VERSION 5.7 ;
  NOWIREEXTENSIONATPIN ON ;
  DIVIDERCHAR "/" ;
  BUSBITCHARS "[]" ;
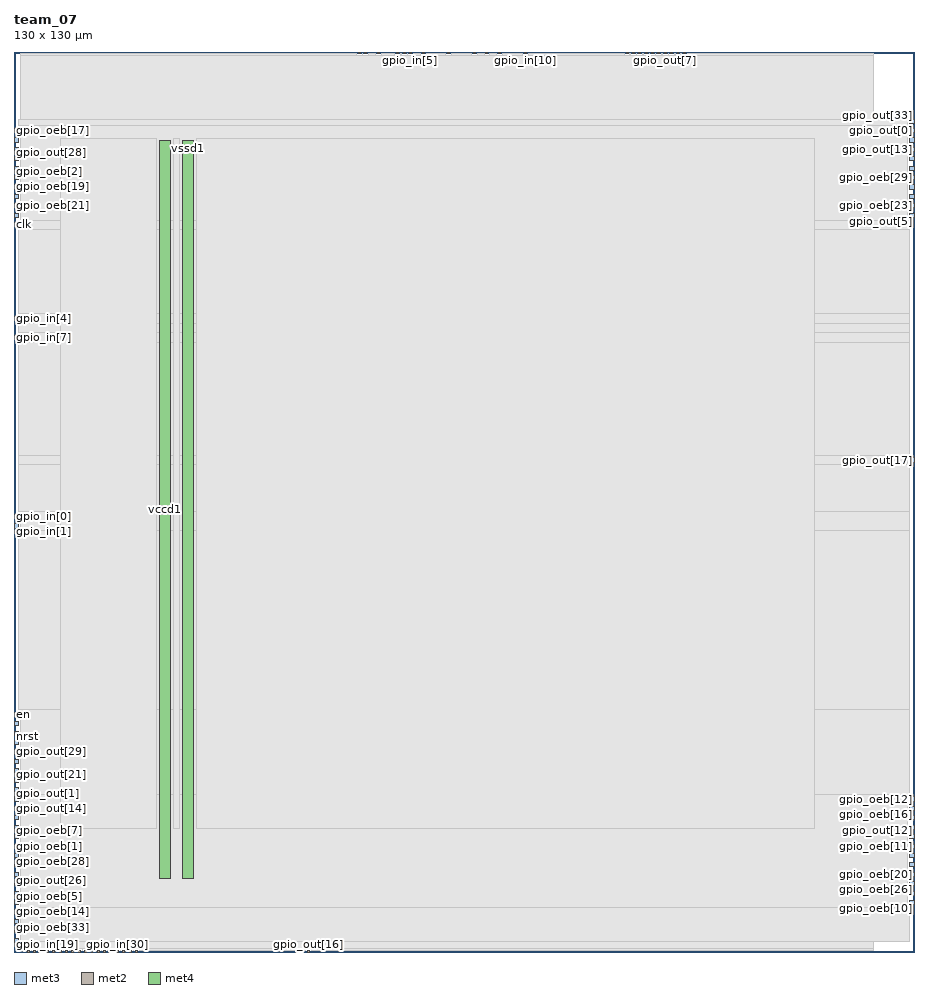
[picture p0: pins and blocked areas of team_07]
MACRO team_07
  CLASS BLOCK ;
  FOREIGN team_07 ;
  ORIGIN 0.000 0.000 ;
  SIZE 130.000 BY 130.000 ;
  PIN clk
    DIRECTION INPUT ;
    USE SIGNAL ;
    ANTENNAGATEAREA 1.286700 ;
    ANTENNADIFFAREA 0.434700 ;
    PORT
      LAYER met3 ;
        RECT 0.000 104.760 0.600 105.360 ;
    END
  END clk
  PIN en
    DIRECTION INPUT ;
    USE SIGNAL ;
    ANTENNAGATEAREA 0.647700 ;
    ANTENNADIFFAREA 0.434700 ;
    PORT
      LAYER met3 ;
        RECT 0.000 34.040 0.600 34.640 ;
    END
  END en
  PIN gpio_in[0]
    DIRECTION INPUT ;
    USE SIGNAL ;
    ANTENNAGATEAREA 0.647700 ;
    ANTENNADIFFAREA 0.434700 ;
    PORT
      LAYER met3 ;
        RECT 0.000 62.600 0.600 63.200 ;
    END
  END gpio_in[0]
  PIN gpio_in[10]
    DIRECTION INPUT ;
    USE SIGNAL ;
    ANTENNAGATEAREA 0.647700 ;
    ANTENNADIFFAREA 0.434700 ;
    PORT
      LAYER met2 ;
        RECT 73.690 129.720 73.970 130.000 ;
    END
  END gpio_in[10]
  PIN gpio_in[11]
    DIRECTION INPUT ;
    USE SIGNAL ;
    ANTENNAGATEAREA 0.647700 ;
    ANTENNADIFFAREA 0.434700 ;
    PORT
      LAYER met2 ;
        RECT 68.170 129.720 68.450 130.000 ;
    END
  END gpio_in[11]
  PIN gpio_in[12]
    DIRECTION INPUT ;
    USE SIGNAL ;
    ANTENNAGATEAREA 0.631200 ;
    ANTENNADIFFAREA 0.434700 ;
    PORT
      LAYER met2 ;
        RECT 70.010 129.720 70.290 130.000 ;
    END
  END gpio_in[12]
  PIN gpio_in[13]
    DIRECTION INPUT ;
    USE SIGNAL ;
    ANTENNAGATEAREA 0.647700 ;
    ANTENNADIFFAREA 0.434700 ;
    PORT
      LAYER met2 ;
        RECT 66.330 129.720 66.610 130.000 ;
    END
  END gpio_in[13]
  PIN gpio_in[14]
    DIRECTION INPUT ;
    USE SIGNAL ;
    ANTENNAGATEAREA 0.647700 ;
    ANTENNADIFFAREA 0.434700 ;
    PORT
      LAYER met2 ;
        RECT 58.970 129.720 59.250 130.000 ;
    END
  END gpio_in[14]
  PIN gpio_in[15]
    DIRECTION INPUT ;
    USE SIGNAL ;
    ANTENNAGATEAREA 0.647700 ;
    ANTENNADIFFAREA 0.434700 ;
    PORT
      LAYER met2 ;
        RECT 50.690 129.720 50.970 130.000 ;
    END
  END gpio_in[15]
  PIN gpio_in[16]
    DIRECTION INPUT ;
    USE SIGNAL ;
    PORT
      LAYER met2 ;
        RECT 1.930 0.000 2.210 0.280 ;
    END
  END gpio_in[16]
  PIN gpio_in[17]
    DIRECTION INPUT ;
    USE SIGNAL ;
    PORT
      LAYER met2 ;
        RECT 2.850 0.000 3.130 0.280 ;
    END
  END gpio_in[17]
  PIN gpio_in[18]
    DIRECTION INPUT ;
    USE SIGNAL ;
    PORT
      LAYER met2 ;
        RECT 3.770 0.000 4.050 0.280 ;
    END
  END gpio_in[18]
  PIN gpio_in[19]
    DIRECTION INPUT ;
    USE SIGNAL ;
    PORT
      LAYER met2 ;
        RECT 4.690 0.000 4.970 0.280 ;
    END
  END gpio_in[19]
  PIN gpio_in[1]
    DIRECTION INPUT ;
    USE SIGNAL ;
    ANTENNAGATEAREA 0.647700 ;
    ANTENNADIFFAREA 0.434700 ;
    PORT
      LAYER met3 ;
        RECT 0.000 61.240 0.600 61.840 ;
    END
  END gpio_in[1]
  PIN gpio_in[20]
    DIRECTION INPUT ;
    USE SIGNAL ;
    PORT
      LAYER met2 ;
        RECT 5.610 0.000 5.890 0.280 ;
    END
  END gpio_in[20]
  PIN gpio_in[21]
    DIRECTION INPUT ;
    USE SIGNAL ;
    PORT
      LAYER met2 ;
        RECT 6.530 0.000 6.810 0.280 ;
    END
  END gpio_in[21]
  PIN gpio_in[22]
    DIRECTION INPUT ;
    USE SIGNAL ;
    PORT
      LAYER met2 ;
        RECT 7.450 0.000 7.730 0.280 ;
    END
  END gpio_in[22]
  PIN gpio_in[23]
    DIRECTION INPUT ;
    USE SIGNAL ;
    PORT
      LAYER met2 ;
        RECT 8.370 0.000 8.650 0.280 ;
    END
  END gpio_in[23]
  PIN gpio_in[24]
    DIRECTION INPUT ;
    USE SIGNAL ;
    PORT
      LAYER met2 ;
        RECT 9.290 0.000 9.570 0.280 ;
    END
  END gpio_in[24]
  PIN gpio_in[25]
    DIRECTION INPUT ;
    USE SIGNAL ;
    PORT
      LAYER met2 ;
        RECT 10.210 0.000 10.490 0.280 ;
    END
  END gpio_in[25]
  PIN gpio_in[26]
    DIRECTION INPUT ;
    USE SIGNAL ;
    PORT
      LAYER met2 ;
        RECT 11.130 0.000 11.410 0.280 ;
    END
  END gpio_in[26]
  PIN gpio_in[27]
    DIRECTION INPUT ;
    USE SIGNAL ;
    PORT
      LAYER met2 ;
        RECT 12.050 0.000 12.330 0.280 ;
    END
  END gpio_in[27]
  PIN gpio_in[28]
    DIRECTION INPUT ;
    USE SIGNAL ;
    PORT
      LAYER met2 ;
        RECT 12.970 0.000 13.250 0.280 ;
    END
  END gpio_in[28]
  PIN gpio_in[29]
    DIRECTION INPUT ;
    USE SIGNAL ;
    PORT
      LAYER met2 ;
        RECT 13.890 0.000 14.170 0.280 ;
    END
  END gpio_in[29]
  PIN gpio_in[2]
    DIRECTION INPUT ;
    USE SIGNAL ;
    ANTENNAGATEAREA 0.647700 ;
    ANTENNADIFFAREA 0.434700 ;
    PORT
      LAYER met2 ;
        RECT 56.210 129.720 56.490 130.000 ;
    END
  END gpio_in[2]
  PIN gpio_in[30]
    DIRECTION INPUT ;
    USE SIGNAL ;
    PORT
      LAYER met2 ;
        RECT 14.810 0.000 15.090 0.280 ;
    END
  END gpio_in[30]
  PIN gpio_in[31]
    DIRECTION INPUT ;
    USE SIGNAL ;
    PORT
      LAYER met2 ;
        RECT 15.730 0.000 16.010 0.280 ;
    END
  END gpio_in[31]
  PIN gpio_in[32]
    DIRECTION INPUT ;
    USE SIGNAL ;
    PORT
      LAYER met2 ;
        RECT 16.650 0.000 16.930 0.280 ;
    END
  END gpio_in[32]
  PIN gpio_in[33]
    DIRECTION INPUT ;
    USE SIGNAL ;
    PORT
      LAYER met2 ;
        RECT 17.570 0.000 17.850 0.280 ;
    END
  END gpio_in[33]
  PIN gpio_in[3]
    DIRECTION INPUT ;
    USE SIGNAL ;
    ANTENNAGATEAREA 0.647700 ;
    ANTENNADIFFAREA 0.434700 ;
    PORT
      LAYER met2 ;
        RECT 55.290 129.720 55.570 130.000 ;
    END
  END gpio_in[3]
  PIN gpio_in[4]
    DIRECTION INPUT ;
    USE SIGNAL ;
    ANTENNAGATEAREA 0.631200 ;
    ANTENNADIFFAREA 0.434700 ;
    PORT
      LAYER met3 ;
        RECT 0.000 91.160 0.600 91.760 ;
    END
  END gpio_in[4]
  PIN gpio_in[5]
    DIRECTION INPUT ;
    USE SIGNAL ;
    ANTENNAGATEAREA 0.647700 ;
    ANTENNADIFFAREA 0.434700 ;
    PORT
      LAYER met2 ;
        RECT 57.130 129.720 57.410 130.000 ;
    END
  END gpio_in[5]
  PIN gpio_in[6]
    DIRECTION INPUT ;
    USE SIGNAL ;
    ANTENNAGATEAREA 0.647700 ;
    ANTENNADIFFAREA 0.434700 ;
    PORT
      LAYER met2 ;
        RECT 52.530 129.720 52.810 130.000 ;
    END
  END gpio_in[6]
  PIN gpio_in[7]
    DIRECTION INPUT ;
    USE SIGNAL ;
    ANTENNAGATEAREA 0.647700 ;
    ANTENNADIFFAREA 0.434700 ;
    PORT
      LAYER met3 ;
        RECT 0.000 88.440 0.600 89.040 ;
    END
  END gpio_in[7]
  PIN gpio_in[8]
    DIRECTION INPUT ;
    USE SIGNAL ;
    ANTENNAGATEAREA 0.647700 ;
    ANTENNADIFFAREA 0.434700 ;
    PORT
      LAYER met2 ;
        RECT 62.650 129.720 62.930 130.000 ;
    END
  END gpio_in[8]
  PIN gpio_in[9]
    DIRECTION INPUT ;
    USE SIGNAL ;
    ANTENNAGATEAREA 0.647700 ;
    ANTENNADIFFAREA 0.434700 ;
    PORT
      LAYER met2 ;
        RECT 49.770 129.720 50.050 130.000 ;
    END
  END gpio_in[9]
  PIN gpio_oeb[0]
    DIRECTION OUTPUT ;
    USE SIGNAL ;
    PORT
      LAYER met2 ;
        RECT 96.690 129.720 96.970 130.000 ;
    END
  END gpio_oeb[0]
  PIN gpio_oeb[10]
    DIRECTION OUTPUT ;
    USE SIGNAL ;
    PORT
      LAYER met3 ;
        RECT 129.400 6.840 130.000 7.440 ;
    END
  END gpio_oeb[10]
  PIN gpio_oeb[11]
    DIRECTION OUTPUT ;
    USE SIGNAL ;
    PORT
      LAYER met3 ;
        RECT 129.400 15.000 130.000 15.600 ;
    END
  END gpio_oeb[11]
  PIN gpio_oeb[12]
    DIRECTION OUTPUT ;
    USE SIGNAL ;
    PORT
      LAYER met3 ;
        RECT 129.400 21.800 130.000 22.400 ;
    END
  END gpio_oeb[12]
  PIN gpio_oeb[13]
    DIRECTION OUTPUT ;
    USE SIGNAL ;
    PORT
      LAYER met3 ;
        RECT 0.000 1.400 0.600 2.000 ;
    END
  END gpio_oeb[13]
  PIN gpio_oeb[14]
    DIRECTION OUTPUT ;
    USE SIGNAL ;
    PORT
      LAYER met3 ;
        RECT 0.000 5.480 0.600 6.080 ;
    END
  END gpio_oeb[14]
  PIN gpio_oeb[15]
    DIRECTION OUTPUT ;
    USE SIGNAL ;
    PORT
      LAYER met3 ;
        RECT 129.400 12.280 130.000 12.880 ;
    END
  END gpio_oeb[15]
  PIN gpio_oeb[16]
    DIRECTION OUTPUT ;
    USE SIGNAL ;
    PORT
      LAYER met3 ;
        RECT 129.400 20.440 130.000 21.040 ;
    END
  END gpio_oeb[16]
  PIN gpio_oeb[17]
    DIRECTION OUTPUT ;
    USE SIGNAL ;
    PORT
      LAYER met3 ;
        RECT 0.000 118.360 0.600 118.960 ;
    END
  END gpio_oeb[17]
  PIN gpio_oeb[18]
    DIRECTION OUTPUT ;
    USE SIGNAL ;
    PORT
      LAYER met3 ;
        RECT 0.000 12.280 0.600 12.880 ;
    END
  END gpio_oeb[18]
  PIN gpio_oeb[19]
    DIRECTION OUTPUT ;
    USE SIGNAL ;
    PORT
      LAYER met3 ;
        RECT 0.000 110.200 0.600 110.800 ;
    END
  END gpio_oeb[19]
  PIN gpio_oeb[1]
    DIRECTION OUTPUT ;
    USE SIGNAL ;
    PORT
      LAYER met3 ;
        RECT 0.000 15.000 0.600 15.600 ;
    END
  END gpio_oeb[1]
  PIN gpio_oeb[20]
    DIRECTION OUTPUT ;
    USE SIGNAL ;
    PORT
      LAYER met3 ;
        RECT 129.400 10.920 130.000 11.520 ;
    END
  END gpio_oeb[20]
  PIN gpio_oeb[21]
    DIRECTION OUTPUT ;
    USE SIGNAL ;
    PORT
      LAYER met3 ;
        RECT 0.000 107.480 0.600 108.080 ;
    END
  END gpio_oeb[21]
  PIN gpio_oeb[22]
    DIRECTION OUTPUT ;
    USE SIGNAL ;
    PORT
      LAYER met3 ;
        RECT 129.400 13.640 130.000 14.240 ;
    END
  END gpio_oeb[22]
  PIN gpio_oeb[23]
    DIRECTION OUTPUT ;
    USE SIGNAL ;
    PORT
      LAYER met3 ;
        RECT 129.400 107.480 130.000 108.080 ;
    END
  END gpio_oeb[23]
  PIN gpio_oeb[24]
    DIRECTION OUTPUT ;
    USE SIGNAL ;
    PORT
      LAYER met3 ;
        RECT 0.000 8.200 0.600 8.800 ;
    END
  END gpio_oeb[24]
  PIN gpio_oeb[25]
    DIRECTION OUTPUT ;
    USE SIGNAL ;
    PORT
      LAYER met3 ;
        RECT 0.000 108.840 0.600 109.440 ;
    END
  END gpio_oeb[25]
  PIN gpio_oeb[26]
    DIRECTION OUTPUT ;
    USE SIGNAL ;
    PORT
      LAYER met3 ;
        RECT 129.400 9.560 130.000 10.160 ;
    END
  END gpio_oeb[26]
  PIN gpio_oeb[27]
    DIRECTION OUTPUT ;
    USE SIGNAL ;
    PORT
      LAYER met3 ;
        RECT 0.000 31.320 0.600 31.920 ;
    END
  END gpio_oeb[27]
  PIN gpio_oeb[28]
    DIRECTION OUTPUT ;
    USE SIGNAL ;
    PORT
      LAYER met3 ;
        RECT 0.000 13.640 0.600 14.240 ;
    END
  END gpio_oeb[28]
  PIN gpio_oeb[29]
    DIRECTION OUTPUT ;
    USE SIGNAL ;
    PORT
      LAYER met3 ;
        RECT 129.400 111.560 130.000 112.160 ;
    END
  END gpio_oeb[29]
  PIN gpio_oeb[2]
    DIRECTION OUTPUT ;
    USE SIGNAL ;
    PORT
      LAYER met3 ;
        RECT 0.000 111.560 0.600 112.160 ;
    END
  END gpio_oeb[2]
  PIN gpio_oeb[30]
    DIRECTION OUTPUT ;
    USE SIGNAL ;
    PORT
      LAYER met3 ;
        RECT 129.400 8.200 130.000 8.800 ;
    END
  END gpio_oeb[30]
  PIN gpio_oeb[31]
    DIRECTION OUTPUT ;
    USE SIGNAL ;
    PORT
      LAYER met3 ;
        RECT 0.000 106.120 0.600 106.720 ;
    END
  END gpio_oeb[31]
  PIN gpio_oeb[32]
    DIRECTION OUTPUT ;
    USE SIGNAL ;
    PORT
      LAYER met2 ;
        RECT 92.090 129.720 92.370 130.000 ;
    END
  END gpio_oeb[32]
  PIN gpio_oeb[33]
    DIRECTION OUTPUT ;
    USE SIGNAL ;
    PORT
      LAYER met3 ;
        RECT 0.000 4.120 0.600 4.720 ;
    END
  END gpio_oeb[33]
  PIN gpio_oeb[3]
    DIRECTION OUTPUT ;
    USE SIGNAL ;
    PORT
      LAYER met2 ;
        RECT 91.170 129.720 91.450 130.000 ;
    END
  END gpio_oeb[3]
  PIN gpio_oeb[4]
    DIRECTION OUTPUT ;
    USE SIGNAL ;
    PORT
      LAYER met2 ;
        RECT 88.410 129.720 88.690 130.000 ;
    END
  END gpio_oeb[4]
  PIN gpio_oeb[5]
    DIRECTION OUTPUT ;
    USE SIGNAL ;
    PORT
      LAYER met3 ;
        RECT 0.000 6.840 0.600 7.440 ;
    END
  END gpio_oeb[5]
  PIN gpio_oeb[6]
    DIRECTION OUTPUT ;
    USE SIGNAL ;
    PORT
      LAYER met2 ;
        RECT 89.330 129.720 89.610 130.000 ;
    END
  END gpio_oeb[6]
  PIN gpio_oeb[7]
    DIRECTION OUTPUT ;
    USE SIGNAL ;
    PORT
      LAYER met3 ;
        RECT 0.000 16.360 0.600 16.960 ;
    END
  END gpio_oeb[7]
  PIN gpio_oeb[8]
    DIRECTION OUTPUT ;
    USE SIGNAL ;
    PORT
      LAYER met3 ;
        RECT 129.400 110.200 130.000 110.800 ;
    END
  END gpio_oeb[8]
  PIN gpio_oeb[9]
    DIRECTION OUTPUT ;
    USE SIGNAL ;
    PORT
      LAYER met3 ;
        RECT 129.400 108.840 130.000 109.440 ;
    END
  END gpio_oeb[9]
  PIN gpio_out[0]
    DIRECTION OUTPUT ;
    USE SIGNAL ;
    PORT
      LAYER met3 ;
        RECT 129.400 118.360 130.000 118.960 ;
    END
  END gpio_out[0]
  PIN gpio_out[10]
    DIRECTION OUTPUT ;
    USE SIGNAL ;
    PORT
      LAYER met2 ;
        RECT 90.250 129.720 90.530 130.000 ;
    END
  END gpio_out[10]
  PIN gpio_out[11]
    DIRECTION OUTPUT ;
    USE SIGNAL ;
    PORT
      LAYER met3 ;
        RECT 0.000 17.720 0.600 18.320 ;
    END
  END gpio_out[11]
  PIN gpio_out[12]
    DIRECTION OUTPUT ;
    USE SIGNAL ;
    PORT
      LAYER met3 ;
        RECT 129.400 16.360 130.000 16.960 ;
    END
  END gpio_out[12]
  PIN gpio_out[13]
    DIRECTION OUTPUT ;
    USE SIGNAL ;
    PORT
      LAYER met3 ;
        RECT 129.400 115.640 130.000 116.240 ;
    END
  END gpio_out[13]
  PIN gpio_out[14]
    DIRECTION OUTPUT ;
    USE SIGNAL ;
    PORT
      LAYER met3 ;
        RECT 0.000 20.440 0.600 21.040 ;
    END
  END gpio_out[14]
  PIN gpio_out[15]
    DIRECTION OUTPUT ;
    USE SIGNAL ;
    PORT
      LAYER met3 ;
        RECT 0.000 112.920 0.600 113.520 ;
    END
  END gpio_out[15]
  PIN gpio_out[16]
    DIRECTION OUTPUT ;
    USE SIGNAL ;
    ANTENNADIFFAREA 0.702900 ;
    PORT
      LAYER met2 ;
        RECT 42.410 0.000 42.690 0.280 ;
    END
  END gpio_out[16]
  PIN gpio_out[17]
    DIRECTION OUTPUT ;
    USE SIGNAL ;
    ANTENNADIFFAREA 0.702900 ;
    PORT
      LAYER met3 ;
        RECT 129.400 70.760 130.000 71.360 ;
    END
  END gpio_out[17]
  PIN gpio_out[18]
    DIRECTION OUTPUT ;
    USE SIGNAL ;
    PORT
      LAYER met3 ;
        RECT 129.400 19.080 130.000 19.680 ;
    END
  END gpio_out[18]
  PIN gpio_out[19]
    DIRECTION OUTPUT ;
    USE SIGNAL ;
    PORT
      LAYER met3 ;
        RECT 129.400 114.280 130.000 114.880 ;
    END
  END gpio_out[19]
  PIN gpio_out[1]
    DIRECTION OUTPUT ;
    USE SIGNAL ;
    PORT
      LAYER met3 ;
        RECT 0.000 21.800 0.600 22.400 ;
    END
  END gpio_out[1]
  PIN gpio_out[20]
    DIRECTION OUTPUT ;
    USE SIGNAL ;
    PORT
      LAYER met3 ;
        RECT 0.000 23.160 0.600 23.760 ;
    END
  END gpio_out[20]
  PIN gpio_out[21]
    DIRECTION OUTPUT ;
    USE SIGNAL ;
    PORT
      LAYER met3 ;
        RECT 0.000 24.520 0.600 25.120 ;
    END
  END gpio_out[21]
  PIN gpio_out[22]
    DIRECTION OUTPUT ;
    USE SIGNAL ;
    PORT
      LAYER met2 ;
        RECT 95.770 129.720 96.050 130.000 ;
    END
  END gpio_out[22]
  PIN gpio_out[23]
    DIRECTION OUTPUT ;
    USE SIGNAL ;
    PORT
      LAYER met3 ;
        RECT 129.400 112.920 130.000 113.520 ;
    END
  END gpio_out[23]
  PIN gpio_out[24]
    DIRECTION OUTPUT ;
    USE SIGNAL ;
    PORT
      LAYER met2 ;
        RECT 93.010 129.720 93.290 130.000 ;
    END
  END gpio_out[24]
  PIN gpio_out[25]
    DIRECTION OUTPUT ;
    USE SIGNAL ;
    PORT
      LAYER met3 ;
        RECT 0.000 25.880 0.600 26.480 ;
    END
  END gpio_out[25]
  PIN gpio_out[26]
    DIRECTION OUTPUT ;
    USE SIGNAL ;
    PORT
      LAYER met3 ;
        RECT 0.000 10.920 0.600 11.520 ;
    END
  END gpio_out[26]
  PIN gpio_out[27]
    DIRECTION OUTPUT ;
    USE SIGNAL ;
    PORT
      LAYER met3 ;
        RECT 0.000 27.240 0.600 27.840 ;
    END
  END gpio_out[27]
  PIN gpio_out[28]
    DIRECTION OUTPUT ;
    USE SIGNAL ;
    PORT
      LAYER met3 ;
        RECT 0.000 114.280 0.600 114.880 ;
    END
  END gpio_out[28]
  PIN gpio_out[29]
    DIRECTION OUTPUT ;
    USE SIGNAL ;
    PORT
      LAYER met3 ;
        RECT 0.000 28.600 0.600 29.200 ;
    END
  END gpio_out[29]
  PIN gpio_out[2]
    DIRECTION OUTPUT ;
    USE SIGNAL ;
    PORT
      LAYER met3 ;
        RECT 0.000 115.640 0.600 116.240 ;
    END
  END gpio_out[2]
  PIN gpio_out[30]
    DIRECTION OUTPUT ;
    USE SIGNAL ;
    PORT
      LAYER met2 ;
        RECT 94.850 129.720 95.130 130.000 ;
    END
  END gpio_out[30]
  PIN gpio_out[31]
    DIRECTION OUTPUT ;
    USE SIGNAL ;
    PORT
      LAYER met3 ;
        RECT 0.000 32.680 0.600 33.280 ;
    END
  END gpio_out[31]
  PIN gpio_out[32]
    DIRECTION OUTPUT ;
    USE SIGNAL ;
    PORT
      LAYER met3 ;
        RECT 129.400 17.720 130.000 18.320 ;
    END
  END gpio_out[32]
  PIN gpio_out[33]
    DIRECTION OUTPUT ;
    USE SIGNAL ;
    PORT
      LAYER met3 ;
        RECT 129.400 119.720 130.000 120.320 ;
    END
  END gpio_out[33]
  PIN gpio_out[3]
    DIRECTION OUTPUT ;
    USE SIGNAL ;
    PORT
      LAYER met3 ;
        RECT 0.000 19.080 0.600 19.680 ;
    END
  END gpio_out[3]
  PIN gpio_out[4]
    DIRECTION OUTPUT ;
    USE SIGNAL ;
    PORT
      LAYER met3 ;
        RECT 0.000 9.560 0.600 10.160 ;
    END
  END gpio_out[4]
  PIN gpio_out[5]
    DIRECTION OUTPUT ;
    USE SIGNAL ;
    PORT
      LAYER met3 ;
        RECT 129.400 106.120 130.000 106.720 ;
    END
  END gpio_out[5]
  PIN gpio_out[6]
    DIRECTION OUTPUT ;
    USE SIGNAL ;
    PORT
      LAYER met3 ;
        RECT 0.000 2.760 0.600 3.360 ;
    END
  END gpio_out[6]
  PIN gpio_out[7]
    DIRECTION OUTPUT ;
    USE SIGNAL ;
    PORT
      LAYER met2 ;
        RECT 93.930 129.720 94.210 130.000 ;
    END
  END gpio_out[7]
  PIN gpio_out[8]
    DIRECTION OUTPUT ;
    USE SIGNAL ;
    PORT
      LAYER met3 ;
        RECT 129.400 117.000 130.000 117.600 ;
    END
  END gpio_out[8]
  PIN gpio_out[9]
    DIRECTION OUTPUT ;
    USE SIGNAL ;
    PORT
      LAYER met3 ;
        RECT 0.000 117.000 0.600 117.600 ;
    END
  END gpio_out[9]
  PIN nrst
    DIRECTION INPUT ;
    USE SIGNAL ;
    ANTENNAGATEAREA 0.647700 ;
    ANTENNADIFFAREA 0.434700 ;
    PORT
      LAYER met3 ;
        RECT 0.000 29.960 0.600 30.560 ;
    END
  END nrst
  PIN vccd1
    DIRECTION INOUT ;
    USE POWER ;
    PORT
      LAYER met4 ;
        RECT 21.040 10.640 22.640 117.200 ;
    END
  END vccd1
  PIN vssd1
    DIRECTION INOUT ;
    USE GROUND ;
    PORT
      LAYER met4 ;
        RECT 24.340 10.640 25.940 117.200 ;
    END
  END vssd1
  OBS
      LAYER nwell ;
        RECT 5.330 10.760 124.390 117.150 ;
      LAYER li1 ;
        RECT 5.520 10.795 124.200 117.045 ;
      LAYER met1 ;
        RECT 0.990 9.560 124.200 117.200 ;
      LAYER met2 ;
        RECT 1.010 129.440 49.490 129.720 ;
        RECT 50.330 129.440 50.410 129.720 ;
        RECT 51.250 129.440 52.250 129.720 ;
        RECT 53.090 129.440 55.010 129.720 ;
        RECT 55.850 129.440 55.930 129.720 ;
        RECT 56.770 129.440 56.850 129.720 ;
        RECT 57.690 129.440 58.690 129.720 ;
        RECT 59.530 129.440 62.370 129.720 ;
        RECT 63.210 129.440 66.050 129.720 ;
        RECT 66.890 129.440 67.890 129.720 ;
        RECT 68.730 129.440 69.730 129.720 ;
        RECT 70.570 129.440 73.410 129.720 ;
        RECT 74.250 129.440 88.130 129.720 ;
        RECT 88.970 129.440 89.050 129.720 ;
        RECT 89.890 129.440 89.970 129.720 ;
        RECT 90.810 129.440 90.890 129.720 ;
        RECT 91.730 129.440 91.810 129.720 ;
        RECT 92.650 129.440 92.730 129.720 ;
        RECT 93.570 129.440 93.650 129.720 ;
        RECT 94.490 129.440 94.570 129.720 ;
        RECT 95.410 129.440 95.490 129.720 ;
        RECT 96.330 129.440 96.410 129.720 ;
        RECT 97.250 129.440 124.110 129.720 ;
        RECT 1.010 0.560 124.110 129.440 ;
        RECT 1.010 0.280 1.650 0.560 ;
        RECT 2.490 0.280 2.570 0.560 ;
        RECT 3.410 0.280 3.490 0.560 ;
        RECT 4.330 0.280 4.410 0.560 ;
        RECT 5.250 0.280 5.330 0.560 ;
        RECT 6.170 0.280 6.250 0.560 ;
        RECT 7.090 0.280 7.170 0.560 ;
        RECT 8.010 0.280 8.090 0.560 ;
        RECT 8.930 0.280 9.010 0.560 ;
        RECT 9.850 0.280 9.930 0.560 ;
        RECT 10.770 0.280 10.850 0.560 ;
        RECT 11.690 0.280 11.770 0.560 ;
        RECT 12.610 0.280 12.690 0.560 ;
        RECT 13.530 0.280 13.610 0.560 ;
        RECT 14.450 0.280 14.530 0.560 ;
        RECT 15.370 0.280 15.450 0.560 ;
        RECT 16.290 0.280 16.370 0.560 ;
        RECT 17.210 0.280 17.290 0.560 ;
        RECT 18.130 0.280 42.130 0.560 ;
        RECT 42.970 0.280 124.110 0.560 ;
      LAYER met3 ;
        RECT 0.600 119.360 129.000 120.185 ;
        RECT 1.000 105.720 129.000 119.360 ;
        RECT 1.000 104.360 129.400 105.720 ;
        RECT 0.600 92.160 129.400 104.360 ;
        RECT 1.000 90.760 129.400 92.160 ;
        RECT 0.600 89.440 129.400 90.760 ;
        RECT 1.000 88.040 129.400 89.440 ;
        RECT 0.600 71.760 129.400 88.040 ;
        RECT 0.600 70.360 129.000 71.760 ;
        RECT 0.600 63.600 129.400 70.360 ;
        RECT 1.000 60.840 129.400 63.600 ;
        RECT 0.600 35.040 129.400 60.840 ;
        RECT 1.000 22.800 129.400 35.040 ;
        RECT 1.000 6.440 129.000 22.800 ;
        RECT 1.000 1.535 129.400 6.440 ;
      LAYER met4 ;
        RECT 6.735 17.855 20.640 117.465 ;
        RECT 23.040 17.855 23.940 117.465 ;
        RECT 26.340 17.855 115.625 117.465 ;
  END
END team_07
END LIBRARY

